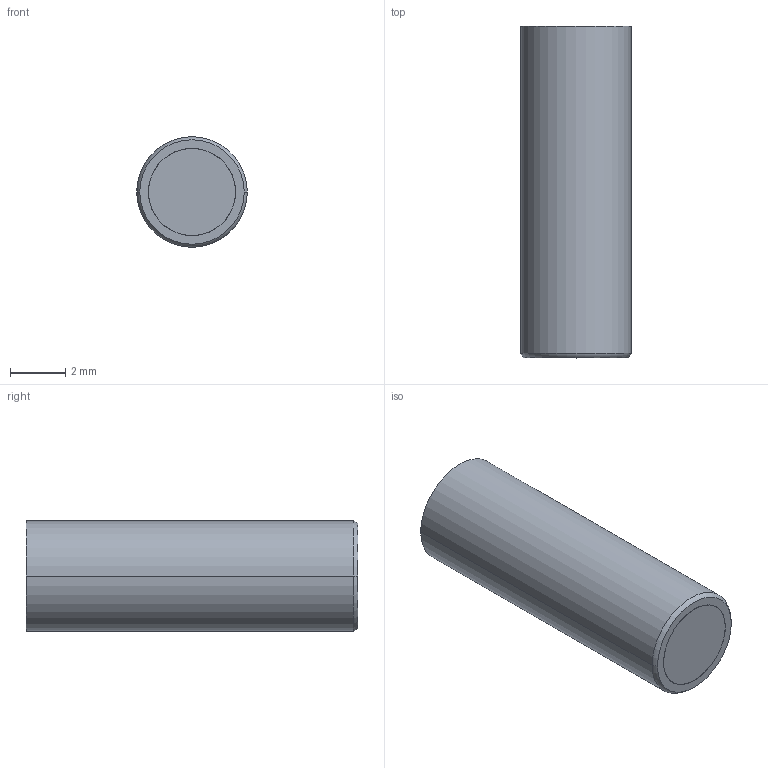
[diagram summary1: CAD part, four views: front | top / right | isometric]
STEP (ISO 10303-21) file: header records copied from the file, then geometry measured from it (millimetres).
FILE_DESCRIPTION (( 'STEP AP214' ), '1' );
FILE_NAME ('FA 042212-20.STEP', '2013-10-01T07:58:57', ( '' ), ( '' ), 'SwSTEP 2.0', 'SolidWorks 2011', '' );
FILE_SCHEMA (( 'AUTOMOTIVE_DESIGN' ));
Length unit declared in the file: millimetre
Products named in the file (6): FA 042212-20; FA 042200-2; IA 227520; FA 042200-1; FA 042200-3; 9FA 042212
Assembly tree (5 placements, depth 2):
  FA 042212-20
    FA 042200-1
    IA 227520
    FA 042200-3
    FA 042200-2
    9FA 042212
Bounding box: 4 x 12 x 4 mm (x, y, z)
Volume: 127.1 mm3; surface area: 505.3 mm2
Topology: 5 solids, 5 shells, 302 faces, 756 edges, 497 vertices
Faces by surface type: cylinder 146, plane 136, cone 14, bspline 4, torus 2
Entity records: 11848 total; most frequent: CARTESIAN_POINT 4011, DIRECTION 1672, ORIENTED_EDGE 1508, EDGE_CURVE 754, AXIS2_PLACEMENT_3D 620, VERTEX_POINT 497, LINE 432, VECTOR 432
One B-rep face of a CAD part: STEP entity #9440.
In plain terms, the planar face has unit normal (-1, 0, 0).
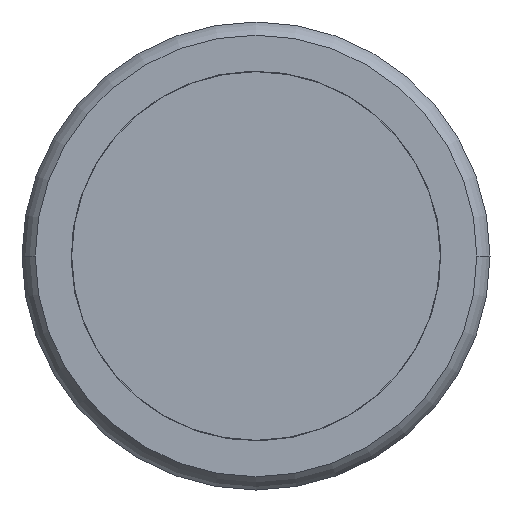
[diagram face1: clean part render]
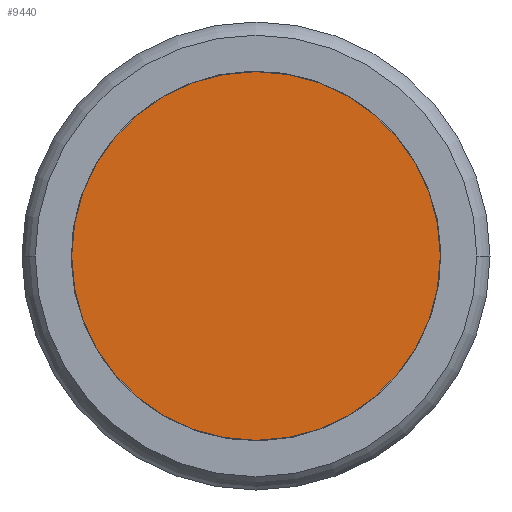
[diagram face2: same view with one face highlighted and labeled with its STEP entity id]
Its self-contained STEP definition (entity closure, numbers rounded to 3 decimals):
#66 = CARTESIAN_POINT ( 'NONE',  ( 0.374, 0., 1.58 ) ) ;
#86 = CARTESIAN_POINT ( 'NONE',  ( 0.374, 0., -1.58 ) ) ;
#3482 = EDGE_LOOP ( 'NONE', ( #4330, #4359 ) ) ;
#4330 = ORIENTED_EDGE ( 'NONE', *, *, #9208, .F. ) ;
#4344 = VERTEX_POINT ( 'NONE', #86 ) ;
#4359 = ORIENTED_EDGE ( 'NONE', *, *, #9113, .F. ) ;
#4376 = VERTEX_POINT ( 'NONE', #66 ) ;
#5361 = CARTESIAN_POINT ( 'NONE',  ( 0.374, 0., 0. ) ) ;
#5374 = DIRECTION ( 'NONE',  ( 1., 0., 0. ) ) ;
#5382 = DIRECTION ( 'NONE',  ( 0., 1., 0. ) ) ;
#5685 = AXIS2_PLACEMENT_3D ( 'NONE', #11024, #11007, #11017 ) ;
#5886 = CIRCLE ( 'NONE', #5889, 1.58 ) ;
#5889 = AXIS2_PLACEMENT_3D ( 'NONE', #5361, #5374, #5382 ) ;
#5995 = AXIS2_PLACEMENT_3D ( 'NONE', #9906, #9894, #9908 ) ;
#6013 = CIRCLE ( 'NONE', #5995, 1.58 ) ;
#9113 = EDGE_CURVE ( 'NONE', #4344, #4376, #5886, .T. ) ;
#9208 = EDGE_CURVE ( 'NONE', #4376, #4344, #6013, .T. ) ;
#9440 = ADVANCED_FACE ( 'NONE', ( #11034 ), #11036, .F. ) ;
#9894 = DIRECTION ( 'NONE',  ( 1., 0., 0. ) ) ;
#9906 = CARTESIAN_POINT ( 'NONE',  ( 0.374, 0., 0. ) ) ;
#9908 = DIRECTION ( 'NONE',  ( 0., 1., 0. ) ) ;
#11007 = DIRECTION ( 'NONE',  ( 1., 0., 0. ) ) ;
#11017 = DIRECTION ( 'NONE',  ( 0., 1., 0. ) ) ;
#11024 = CARTESIAN_POINT ( 'NONE',  ( 0.374, 1.735, -10. ) ) ;
#11034 = FACE_OUTER_BOUND ( 'NONE', #3482, .T. ) ;
#11036 = PLANE ( 'NONE',  #5685 ) ;
